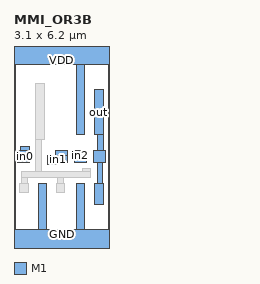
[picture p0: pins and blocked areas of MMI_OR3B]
MACRO MMI_OR3B
	CLASS CORE ;
	FOREIGN MMI_OR3B 0 0 ;
	SIZE 3.1 BY 6.2 ;
	SYMMETRY X Y ;
	SITE CORE1 ;
	PIN out
		DIRECTION output ;
		USE SIGNAL ;
		PORT
			LAYER M1 ;
			RECT 2.625 3.505 2.905 4.975 ;
			LAYER M1 ;
			RECT 2.715 2.98 2.905 3.505 ;
			LAYER M1 ;
			RECT 2.6 2.6 2.98 2.98 ;
			LAYER M1 ;
			RECT 2.71 1.915 2.9 2.6 ;
			LAYER M1 ;
			RECT 2.625 1.215 2.905 1.915 ;
		END
		AntennaDiffArea 0.91245 ;
	END out
	PIN in1
		DIRECTION input ;
		USE SIGNAL ;
		PORT
			LAYER M1 ;
			RECT 1.36 2.815 1.74 2.98 ;
			LAYER M1 ;
			RECT 1.1 2.6 1.74 2.815 ;
			LAYER M1 ;
			RECT 1.1 2.535 1.38 2.6 ;
		END
		AntennaGateArea 0.405 ;
	END in1
	PIN GND
		DIRECTION inout ;
		USE GROUND ;
		PORT
			LAYER M1 ;
			RECT 0.785 0.42 1.065 1.915 ;
			LAYER M1 ;
			RECT 2.035 0.42 2.315 1.915 ;
			LAYER M1 ;
			RECT 0 -0.42 3.1 0.42 ;
		END
	END GND
	PIN in2
		DIRECTION input ;
		USE SIGNAL ;
		PORT
			LAYER M1 ;
			RECT 1.98 2.975 2.36 2.98 ;
			LAYER M1 ;
			RECT 1.94 2.695 2.36 2.975 ;
			LAYER M1 ;
			RECT 1.98 2.6 2.36 2.695 ;
		END
		AntennaGateArea 0.405 ;
	END in2
	PIN VDD
		DIRECTION inout ;
		USE POWER ;
		PORT
			LAYER M1 ;
			RECT 0 5.78 3.1 6.62 ;
			LAYER M1 ;
			RECT 2.035 3.505 2.315 5.78 ;
		END
	END VDD
	PIN in0
		DIRECTION input ;
		USE SIGNAL ;
		PORT
			LAYER M1 ;
			RECT 0.215 2.98 0.495 3.125 ;
			LAYER M1 ;
			RECT 0.12 2.6 0.5 2.98 ;
		END
		AntennaGateArea 0.405 ;
	END in0
	OBS
		LAYER M1 ;
		RECT 0.705 3.345 0.985 5.185 ;
		LAYER M1 ;
		RECT 0.705 2.315 0.895 3.345 ;
		LAYER M1 ;
		RECT 2.23 2.315 2.51 2.4 ;
		LAYER M1 ;
		RECT 0.23 2.12 2.51 2.315 ;
		LAYER M1 ;
		RECT 0.23 1.915 0.425 2.12 ;
		LAYER M1 ;
		RECT 1.415 1.915 1.61 2.12 ;
		LAYER M1 ;
		RECT 0.195 1.6 0.475 1.915 ;
		LAYER M1 ;
		RECT 1.375 1.6 1.655 1.915 ;
	END
END MMI_OR3B
